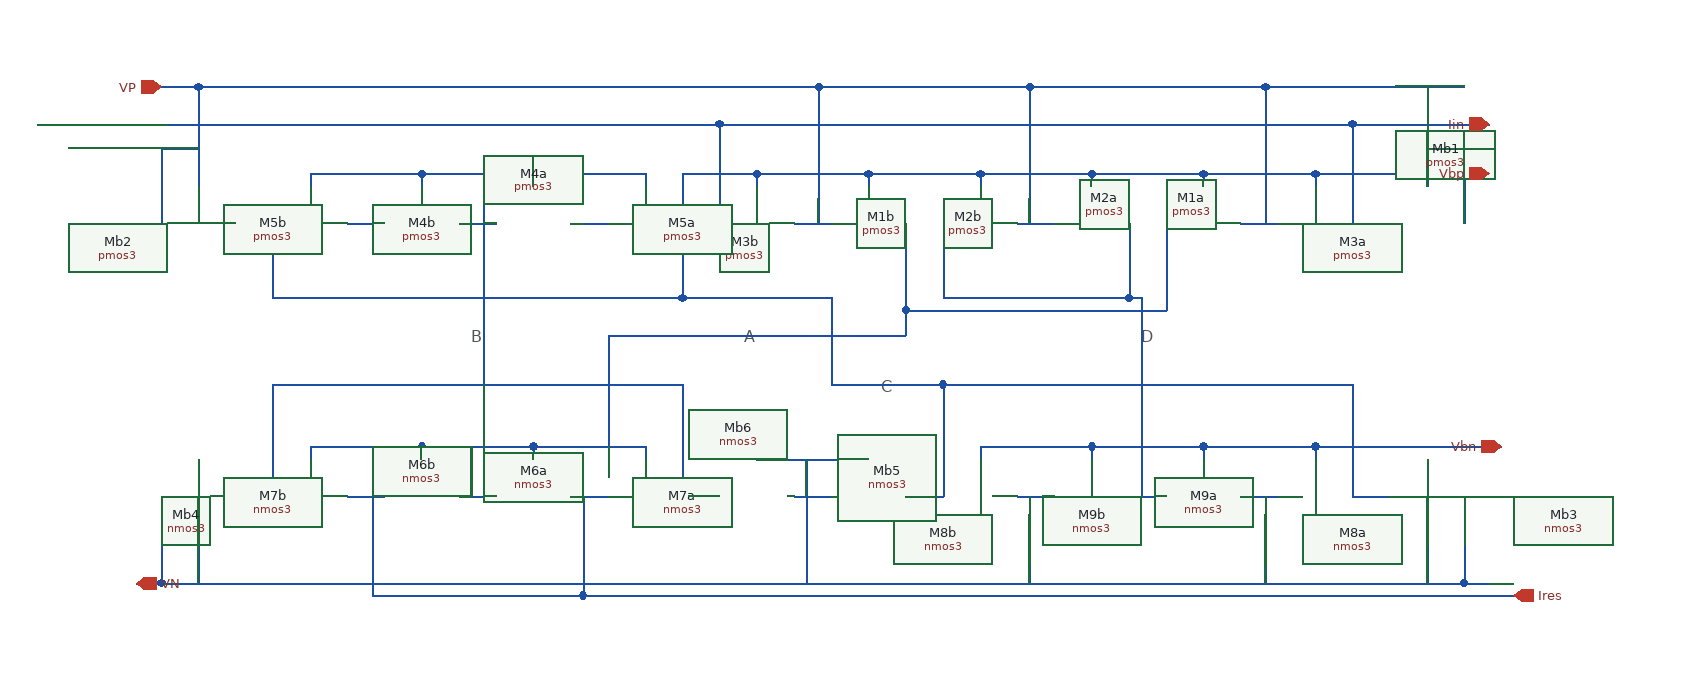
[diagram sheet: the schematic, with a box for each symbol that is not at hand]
v {xschem version=3.4.3 file_version=1.2
}
G {}
K {}
V {}
S {}
E {}
T {D} 620 -20 0 1 0.4 0.4 {}
T {A} 300 -20 0 1 0.4 0.4 {}
T {B} 80 -20 0 1 0.4 0.4 {}
T {C} 410 20 0 1 0.4 0.4 {}
N 670 -140 670 -130 {
lab=Vbp}
N 580 -140 670 -140 {
lab=Vbp}
N 580 -140 580 -130 {
lab=Vbp}
N 490 -140 490 -130 {
lab=Vbp}
N 400 -140 490 -140 {
lab=Vbp}
N 400 -140 400 -130 {
lab=Vbp}
N 490 -140 580 -140 {
lab=Vbp}
N 520 -100 550 -100 {
lab=VP}
N 610 -100 610 -40 {
lab=Vbn}
N 460 -40 610 -40 {
lab=Vbn}
N 460 -100 460 -40 {
lab=Vbn}
N 530 -210 530 -100 {
lab=VP}
N 760 -140 760 -130 {
lab=Vbp}
N 670 -140 760 -140 {
lab=Vbp}
N 310 -140 400 -140 {
lab=Vbp}
N 310 -140 310 -130 {
lab=Vbp}
N 700 -100 730 -100 {
lab=VP}
N 340 -100 370 -100 {
lab=VP}
N 640 -100 640 -30 {
lab=#net1}
N 430 -30 640 -30 {
lab=#net1}
N 430 -100 430 -30 {
lab=#net1}
N 720 -210 720 -100 {
lab=VP}
N 530 -210 720 -210 {
lab=VP}
N 360 -210 530 -210 {
lab=VP}
N 360 -210 360 -100 {
lab=VP}
N 720 -210 810 -210 {
lab=VP}
N 790 -180 790 -100 {
lab=Iin}
N 280 -180 790 -180 {
lab=Iin}
N 280 -180 280 -100 {
lab=Iin}
N 190 -180 280 -180 {
lab=Iin}
N 810 -210 880 -210 {
lab=VP}
N 790 -100 820 -100 {
lab=Iin}
N 850 -210 850 -130 {
lab=VP}
N 880 -160 880 -100 {
lab=VP}
N 850 -160 880 -160 {
lab=VP}
N 70 -100 100 -100 {
lab=#net2}
N 160 -100 190 -100 {
lab=#net3}
N -20 -100 10 -100 {
lab=#net4}
N 220 -140 220 -130 {
lab=#net2}
N 130 -140 220 -140 {
lab=#net2}
N 130 -140 130 -130 {
lab=#net2}
N 40 -140 130 -140 {
lab=#net2}
N 40 -140 40 -130 {
lab=#net2}
N -50 -140 40 -140 {
lab=#net2}
N 90 -140 90 -100 {
lab=#net2}
N 250 -100 250 -40 {
lab=Vbp}
N -80 -40 250 -40 {
lab=Vbp}
N -80 -100 -80 -40 {
lab=Vbp}
N 90 -100 90 0 {
lab=#net2}
N -50 -140 -50 -130 {
lab=#net2}
N -110 -100 -80 -100 {
lab=Vbp}
N -130 -210 360 -210 {
lab=VP}
N -140 -210 -130 -210 {
lab=VP}
N -140 -210 -140 -130 {
lab=VP}
N -170 -160 -140 -160 {
lab=VP}
N -170 -160 -170 -100 {
lab=VP}
N -230 -180 190 -180 {
lab=Iin}
N 700 120 730 120 {
lab=VP}
N 610 120 640 120 {
lab=Vbn}
N 520 120 550 120 {
lab=VP}
N 760 80 760 90 {
lab=Vbn}
N 670 80 760 80 {
lab=Vbn}
N 670 80 670 90 {
lab=Vbn}
N 580 80 670 80 {
lab=Vbn}
N 580 80 580 90 {
lab=Vbn}
N 490 80 580 80 {
lab=Vbn}
N 490 80 490 90 {
lab=Vbn}
N 620 80 620 120 {
lab=Vbn}
N 610 -40 620 -40 {
lab=Vbn}
N 620 -40 620 80 {
lab=Vbn}
N 790 30 790 120 {
lab=Vbp}
N 460 30 790 30 {
lab=Vbp}
N 460 30 460 120 {
lab=Vbp}
N 160 120 190 120 {
lab=VP}
N 70 120 100 120 {
lab=#net1}
N -20 120 10 120 {
lab=VP}
N 220 80 220 90 {
lab=#net1}
N 130 80 220 80 {
lab=#net1}
N 130 80 130 90 {
lab=#net1}
N 40 80 130 80 {
lab=#net1}
N 40 80 40 90 {
lab=#net1}
N -50 80 40 80 {
lab=#net1}
N -50 80 -50 90 {
lab=#net1}
N 80 80 80 120 {
lab=#net1}
N 250 30 250 120 {
lab=#net2}
N -80 30 250 30 {
lab=#net2}
N -80 30 -80 120 {
lab=#net2}
N 250 -40 370 -40 {
lab=Vbp}
N 370 30 460 30 {
lab=Vbp}
N 430 -30 430 -10 {
lab=#net1}
N 250 -10 430 -10 {
lab=#net1}
N 190 -10 250 -10 {
lab=#net1}
N 190 -10 190 80 {
lab=#net1}
N 90 0 90 30 {
lab=#net2}
N -110 120 -80 120 {
lab=#net2}
N 790 120 820 120 {
lab=Vbp}
N 880 120 880 190 {
lab=VP}
N -170 190 880 190 {
lab=VP}
N -170 120 -170 190 {
lab=VP}
N 880 190 900 190 {
lab=VP}
N 850 90 850 190 {
lab=VP}
N -140 90 -140 190 {
lab=VP}
N 720 120 720 190 {
lab=VP}
N 530 120 530 190 {
lab=VP}
N 250 -140 310 -140 {
lab=Vbp}
N 250 -140 250 -100 {
lab=Vbp}
N 430 120 460 120 {
lab=Vbp}
N 340 120 370 120 {
lab=VP}
N 250 120 280 120 {
lab=#net2}
N 310 90 400 90 {
lab=VP}
N 350 90 350 190 {
lab=VP}
N 350 120 350 190 {
lab=VP}
N -270 -180 -230 -180 {
lab=Iin}
N -170 -210 -140 -210 {
lab=VP}
N 790 -180 900 -180 {
lab=Iin}
N 760 -140 900 -140 {
lab=Vbp}
N 760 80 910 80 {
lab=Vbn}
N -190 190 -170 190 {
lab=VP}
N 0 120 0 200 {}
N 0 200 170 200 {}
N 170 120 170 200 {}
N 170 200 920 200 {}
N 370 -40 370 30 {}
C {madvlsi/pmos3.sym} 670 -100 3 1 {name=M1a
L=8
W=12
body=VDD
nf=1
mult=1
ad="'int((nf+1)/2) * W/nf * 0.29'" 
pd="'2*int((nf+1)/2) * (W/nf + 0.29)'"
as="'int((nf+2)/2) * W/nf * 0.29'" 
ps="'2*int((nf+2)/2) * (W/nf + 0.29)'"
nrd="'0.29 / W'" nrs="'0.29 / W'"
sa=0 sb=0 sd=0
model=pfet_01v8
spiceprefix=X
}
C {madvlsi/pmos3.sym} 400 -100 3 1 {name=M1b
L=8
W=12
body=VDD
nf=1
mult=1
ad="'int((nf+1)/2) * W/nf * 0.29'" 
pd="'2*int((nf+1)/2) * (W/nf + 0.29)'"
as="'int((nf+2)/2) * W/nf * 0.29'" 
ps="'2*int((nf+2)/2) * (W/nf + 0.29)'"
nrd="'0.29 / W'" nrs="'0.29 / W'"
sa=0 sb=0 sd=0
model=pfet_01v8
spiceprefix=X
}
C {madvlsi/pmos3.sym} 580 -100 3 1 {name=M2a
L=8
W=12
body=VDD
nf=1
mult=1
ad="'int((nf+1)/2) * W/nf * 0.29'" 
pd="'2*int((nf+1)/2) * (W/nf + 0.29)'"
as="'int((nf+2)/2) * W/nf * 0.29'" 
ps="'2*int((nf+2)/2) * (W/nf + 0.29)'"
nrd="'0.29 / W'" nrs="'0.29 / W'"
sa=0 sb=0 sd=0
model=pfet_01v8
spiceprefix=X
}
C {madvlsi/pmos3.sym} 490 -100 3 1 {name=M2b
L=8
W=12
body=VDD
nf=1
mult=1
ad="'int((nf+1)/2) * W/nf * 0.29'" 
pd="'2*int((nf+1)/2) * (W/nf + 0.29)'"
as="'int((nf+2)/2) * W/nf * 0.29'" 
ps="'2*int((nf+2)/2) * (W/nf + 0.29)'"
nrd="'0.29 / W'" nrs="'0.29 / W'"
sa=0 sb=0 sd=0
model=pfet_01v8
spiceprefix=X
}
C {madvlsi/pmos3.sym} 760 -100 3 1 {name=M3a
L=8
W=12
body=VDD
nf=1
mult=1
ad="'int((nf+1)/2) * W/nf * 0.29'" 
pd="'2*int((nf+1)/2) * (W/nf + 0.29)'"
as="'int((nf+2)/2) * W/nf * 0.29'" 
ps="'2*int((nf+2)/2) * (W/nf + 0.29)'"
nrd="'0.29 / W'" nrs="'0.29 / W'"
sa=0 sb=0 sd=0
model=pfet_01v8
spiceprefix=X
}
C {madvlsi/pmos3.sym} 310 -100 3 1 {name=M3b
L=8
W=12
body=VDD
nf=1
mult=1
ad="'int((nf+1)/2) * W/nf * 0.29'" 
pd="'2*int((nf+1)/2) * (W/nf + 0.29)'"
as="'int((nf+2)/2) * W/nf * 0.29'" 
ps="'2*int((nf+2)/2) * (W/nf + 0.29)'"
nrd="'0.29 / W'" nrs="'0.29 / W'"
sa=0 sb=0 sd=0
model=pfet_01v8
spiceprefix=X
}
C {madvlsi/pmos3.sym} 850 -100 3 1 {name=Mb1
L=8
W=12
body=VDD
nf=1
mult=1
ad="'int((nf+1)/2) * W/nf * 0.29'" 
pd="'2*int((nf+1)/2) * (W/nf + 0.29)'"
as="'int((nf+2)/2) * W/nf * 0.29'" 
ps="'2*int((nf+2)/2) * (W/nf + 0.29)'"
nrd="'0.29 / W'" nrs="'0.29 / W'"
sa=0 sb=0 sd=0
model=pfet_01v8
spiceprefix=X
}
C {madvlsi/pmos3.sym} 40 -100 3 1 {name=M4b
L=8
W=12
body=VDD
nf=1
mult=1
ad="'int((nf+1)/2) * W/nf * 0.29'" 
pd="'2*int((nf+1)/2) * (W/nf + 0.29)'"
as="'int((nf+2)/2) * W/nf * 0.29'" 
ps="'2*int((nf+2)/2) * (W/nf + 0.29)'"
nrd="'0.29 / W'" nrs="'0.29 / W'"
sa=0 sb=0 sd=0
model=pfet_01v8
spiceprefix=X
}
C {madvlsi/pmos3.sym} 130 -100 3 1 {name=M4a
L=8
W=12
body=VDD
nf=1
mult=1
ad="'int((nf+1)/2) * W/nf * 0.29'" 
pd="'2*int((nf+1)/2) * (W/nf + 0.29)'"
as="'int((nf+2)/2) * W/nf * 0.29'" 
ps="'2*int((nf+2)/2) * (W/nf + 0.29)'"
nrd="'0.29 / W'" nrs="'0.29 / W'"
sa=0 sb=0 sd=0
model=pfet_01v8
spiceprefix=X
}
C {madvlsi/pmos3.sym} 220 -100 3 1 {name=M5a
L=8
W=12
body=VDD
nf=1
mult=1
ad="'int((nf+1)/2) * W/nf * 0.29'" 
pd="'2*int((nf+1)/2) * (W/nf + 0.29)'"
as="'int((nf+2)/2) * W/nf * 0.29'" 
ps="'2*int((nf+2)/2) * (W/nf + 0.29)'"
nrd="'0.29 / W'" nrs="'0.29 / W'"
sa=0 sb=0 sd=0
model=pfet_01v8
spiceprefix=X
}
C {madvlsi/pmos3.sym} -50 -100 3 1 {name=M5b
L=8
W=12
body=VDD
nf=1
mult=1
ad="'int((nf+1)/2) * W/nf * 0.29'" 
pd="'2*int((nf+1)/2) * (W/nf + 0.29)'"
as="'int((nf+2)/2) * W/nf * 0.29'" 
ps="'2*int((nf+2)/2) * (W/nf + 0.29)'"
nrd="'0.29 / W'" nrs="'0.29 / W'"
sa=0 sb=0 sd=0
model=pfet_01v8
spiceprefix=X
}
C {madvlsi/pmos3.sym} -140 -100 3 1 {name=Mb2
L=8
W=12
body=VDD
nf=1
mult=1
ad="'int((nf+1)/2) * W/nf * 0.29'" 
pd="'2*int((nf+1)/2) * (W/nf + 0.29)'"
as="'int((nf+2)/2) * W/nf * 0.29'" 
ps="'2*int((nf+2)/2) * (W/nf + 0.29)'"
nrd="'0.29 / W'" nrs="'0.29 / W'"
sa=0 sb=0 sd=0
model=pfet_01v8
spiceprefix=X
}
C {madvlsi/nmos3.sym} 760 120 3 1 {name=M8a
L=8
W=12
body=GND
nf=1
mult=1
ad="'int((nf+1)/2) * W/nf * 0.29'" 
pd="'2*int((nf+1)/2) * (W/nf + 0.29)'"
as="'int((nf+2)/2) * W/nf * 0.29'" 
ps="'2*int((nf+2)/2) * (W/nf + 0.29)'"
nrd="'0.29 / W'" nrs="'0.29 / W'"
sa=0 sb=0 sd=0
model=nfet_01v8
spiceprefix=X
}
C {madvlsi/nmos3.sym} 490 120 3 1 {name=M8b
L=8
W=12
body=GND
nf=1
mult=1
ad="'int((nf+1)/2) * W/nf * 0.29'" 
pd="'2*int((nf+1)/2) * (W/nf + 0.29)'"
as="'int((nf+2)/2) * W/nf * 0.29'" 
ps="'2*int((nf+2)/2) * (W/nf + 0.29)'"
nrd="'0.29 / W'" nrs="'0.29 / W'"
sa=0 sb=0 sd=0
model=nfet_01v8
spiceprefix=X
}
C {madvlsi/nmos3.sym} 670 120 3 1 {name=M9a
L=8
W=12
body=GND
nf=1
mult=1
ad="'int((nf+1)/2) * W/nf * 0.29'" 
pd="'2*int((nf+1)/2) * (W/nf + 0.29)'"
as="'int((nf+2)/2) * W/nf * 0.29'" 
ps="'2*int((nf+2)/2) * (W/nf + 0.29)'"
nrd="'0.29 / W'" nrs="'0.29 / W'"
sa=0 sb=0 sd=0
model=nfet_01v8
spiceprefix=X
}
C {madvlsi/nmos3.sym} 580 120 3 1 {name=M9b
L=8
W=12
body=GND
nf=1
mult=1
ad="'int((nf+1)/2) * W/nf * 0.29'" 
pd="'2*int((nf+1)/2) * (W/nf + 0.29)'"
as="'int((nf+2)/2) * W/nf * 0.29'" 
ps="'2*int((nf+2)/2) * (W/nf + 0.29)'"
nrd="'0.29 / W'" nrs="'0.29 / W'"
sa=0 sb=0 sd=0
model=nfet_01v8
spiceprefix=X
}
C {madvlsi/nmos3.sym} 850 120 3 1 {name=Mb3
L=8
W=12
body=GND
nf=1
mult=1
ad="'int((nf+1)/2) * W/nf * 0.29'" 
pd="'2*int((nf+1)/2) * (W/nf + 0.29)'"
as="'int((nf+2)/2) * W/nf * 0.29'" 
ps="'2*int((nf+2)/2) * (W/nf + 0.29)'"
nrd="'0.29 / W'" nrs="'0.29 / W'"
sa=0 sb=0 sd=0
model=nfet_01v8
spiceprefix=X
}
C {madvlsi/nmos3.sym} -140 120 3 1 {name=Mb4
L=8
W=12
body=GND
nf=1
mult=1
ad="'int((nf+1)/2) * W/nf * 0.29'" 
pd="'2*int((nf+1)/2) * (W/nf + 0.29)'"
as="'int((nf+2)/2) * W/nf * 0.29'" 
ps="'2*int((nf+2)/2) * (W/nf + 0.29)'"
nrd="'0.29 / W'" nrs="'0.29 / W'"
sa=0 sb=0 sd=0
model=nfet_01v8
spiceprefix=X
}
C {madvlsi/nmos3.sym} 220 120 3 1 {name=M7a
L=8
W=12
body=GND
nf=1
mult=1
ad="'int((nf+1)/2) * W/nf * 0.29'" 
pd="'2*int((nf+1)/2) * (W/nf + 0.29)'"
as="'int((nf+2)/2) * W/nf * 0.29'" 
ps="'2*int((nf+2)/2) * (W/nf + 0.29)'"
nrd="'0.29 / W'" nrs="'0.29 / W'"
sa=0 sb=0 sd=0
model=nfet_01v8
spiceprefix=X
}
C {madvlsi/nmos3.sym} -50 120 3 1 {name=M7b
L=8
W=12
body=GND
nf=1
mult=1
ad="'int((nf+1)/2) * W/nf * 0.29'" 
pd="'2*int((nf+1)/2) * (W/nf + 0.29)'"
as="'int((nf+2)/2) * W/nf * 0.29'" 
ps="'2*int((nf+2)/2) * (W/nf + 0.29)'"
nrd="'0.29 / W'" nrs="'0.29 / W'"
sa=0 sb=0 sd=0
model=nfet_01v8
spiceprefix=X
}
C {madvlsi/nmos3.sym} 130 120 3 1 {name=M6a
L=8
W=12
body=GND
nf=1
mult=1
ad="'int((nf+1)/2) * W/nf * 0.29'" 
pd="'2*int((nf+1)/2) * (W/nf + 0.29)'"
as="'int((nf+2)/2) * W/nf * 0.29'" 
ps="'2*int((nf+2)/2) * (W/nf + 0.29)'"
nrd="'0.29 / W'" nrs="'0.29 / W'"
sa=0 sb=0 sd=0
model=nfet_01v8
spiceprefix=X
}
C {madvlsi/nmos3.sym} 40 120 3 1 {name=M6b
L=8
W=12
body=GND
nf=1
mult=1
ad="'int((nf+1)/2) * W/nf * 0.29'" 
pd="'2*int((nf+1)/2) * (W/nf + 0.29)'"
as="'int((nf+2)/2) * W/nf * 0.29'" 
ps="'2*int((nf+2)/2) * (W/nf + 0.29)'"
nrd="'0.29 / W'" nrs="'0.29 / W'"
sa=0 sb=0 sd=0
model=nfet_01v8
spiceprefix=X
}
C {madvlsi/nmos3.sym} 400 120 3 1 {name=Mb5
L=8
W=12
body=GND
nf=1
mult=1
ad="'int((nf+1)/2) * W/nf * 0.29'" 
pd="'2*int((nf+1)/2) * (W/nf + 0.29)'"
as="'int((nf+2)/2) * W/nf * 0.29'" 
ps="'2*int((nf+2)/2) * (W/nf + 0.29)'"
nrd="'0.29 / W'" nrs="'0.29 / W'"
sa=0 sb=0 sd=0
model=nfet_01v8
spiceprefix=X
}
C {madvlsi/nmos3.sym} 310 120 3 1 {name=Mb6
L=8
W=12
body=GND
nf=1
mult=1
ad="'int((nf+1)/2) * W/nf * 0.29'" 
pd="'2*int((nf+1)/2) * (W/nf + 0.29)'"
as="'int((nf+2)/2) * W/nf * 0.29'" 
ps="'2*int((nf+2)/2) * (W/nf + 0.29)'"
nrd="'0.29 / W'" nrs="'0.29 / W'"
sa=0 sb=0 sd=0
model=nfet_01v8
spiceprefix=X
}
C {devices/iopin.sym} -170 -210 2 0 {name=p4 lab=VP}
C {devices/opin.sym} 900 -180 2 1 {name=p2 lab=Iin}
C {devices/opin.sym} 900 -140 2 1 {name=p3 lab=Vbp}
C {devices/opin.sym} 910 80 2 1 {name=p5 lab=Vbn}
C {devices/iopin.sym} -190 190 0 1 {name=p1 lab=VN}
C {devices/opin.sym} 920 200 0 0 {name=p6 lab=Ires}
